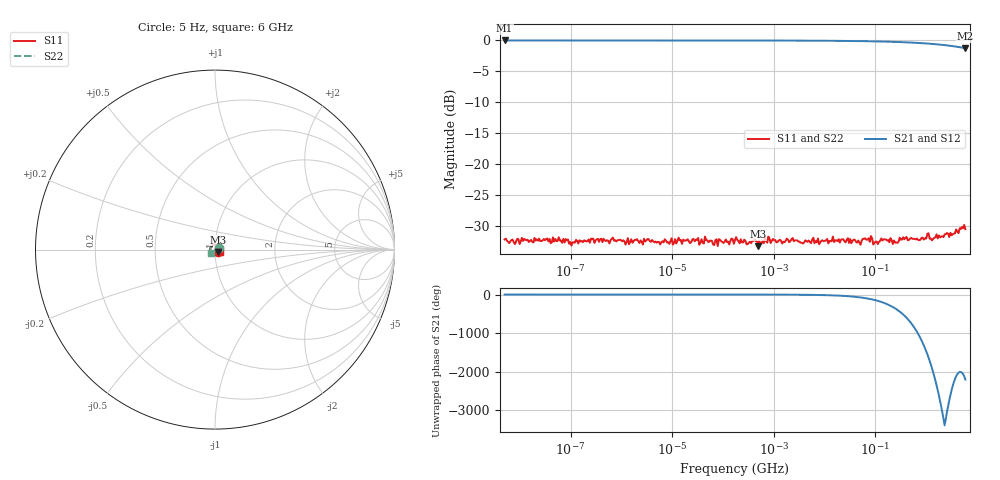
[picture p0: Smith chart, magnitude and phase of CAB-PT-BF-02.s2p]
! CAL-ELEKTRA — DATOS SINTÉTICOS DE EJEMPLO: no son una medida real.
! Cable simulado CAB-PT-BF-02: 1.0 m, 5 Hz – 6 GHz
# HZ S RI R 50
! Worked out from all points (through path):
!   401 points, 5 Hz to 6 GHz, reference 50 ohm
!   highest |S21| = 0.00 dB at 5 Hz (marker M1); lowest = -1.3 dB at 6 GHz (marker M2)
!   lowest |S11| = -33.3 dB at 492.6 kHz (marker M3), VSWR 1.04, Z = 51.7 - j1.44 ohm
!   |S11| at or under -10 dB: start of sweep to end of sweep
!   |S22| runs from -33.3 to -29.9 dB; largest |S21 - S12| = 0
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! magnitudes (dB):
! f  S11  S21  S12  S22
! 5 Hz  -32.3  0.0  0.0  -32.3
! 79.79 Hz  -32.2  0.0  0.0  -32.2
! 103.6 Hz  -33.2  0.0  0.0  -33.2
! 165.9 Hz  -32.5  0.0  0.0  -32.5
! 3.096 kHz  -32.4  0.0  0.0  -32.4
! 5.502 kHz  -32.6  0.0  0.0  -32.6
! 29.3 kHz  -32.3  0.0  0.0  -32.3
! 71.24 kHz  -32.3  0.0  0.0  -32.3
! 173.2 kHz  -32.3  0.0  0.0  -32.3
! 492.6 kHz  -33.3  0.0  0.0  -33.3
! 748.3 kHz  -32.8  0.0  0.0  -32.8
! 5.745 MHz  -32.3  0.0  0.0  -32.3
! 46.48 MHz  -32.4  -0.1  -0.1  -32.4
! 78.38 MHz  -32.6  -0.1  -0.1  -32.6
! 101.8 MHz  -32.6  -0.1  -0.1  -32.6
! 190.6 MHz  -32.7  -0.2  -0.2  -32.7
! 247.5 MHz  -32.8  -0.2  -0.2  -32.8
! 376 MHz  -32.2  -0.3  -0.3  -32.2
! 703.9 MHz  -32.3  -0.4  -0.4  -32.3
! 1.069 GHz  -31.3  -0.5  -0.5  -31.3
! 1.318 GHz  -32.4  -0.6  -0.6  -32.4
! 6 GHz  -30.6  -1.3  -1.3  -30.6
